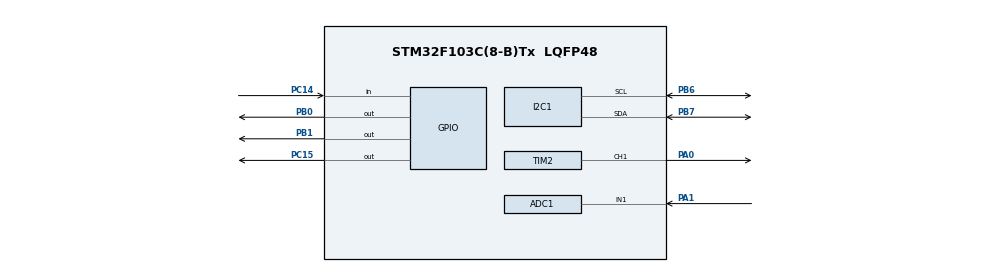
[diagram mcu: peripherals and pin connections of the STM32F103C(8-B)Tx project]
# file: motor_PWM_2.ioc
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ADC1.Channel-2\#ChannelRegularConversion=ADC_CHANNEL_1
ADC1.ContinuousConvMode=ENABLE
ADC1.NbrOfConversion=1
ADC1.NbrOfConversionFlag=1
ADC1.Rank-2\#ChannelRegularConversion=1
ADC1.SamplingTime-2\#ChannelRegularConversion=ADC_SAMPLETIME_1CYCLE_5
ADC1.master=1
Mcu.Family=STM32F1
Mcu.Name=STM32F103C(8-B)Tx
Mcu.Package=LQFP48
NVIC.PriorityGroup=NVIC_PRIORITYGROUP_4
PA0-WKUP.Signal=S_TIM2_CH1_ETR
PA1.Signal=ADCx_IN1
PA13.Mode=Serial_Wire
PA13.Signal=SYS_JTMS-SWDIO
PA14.Mode=Serial_Wire
PA14.Signal=SYS_JTCK-SWCLK
PB0.Signal=GPIO_Output
PB1.Signal=GPIO_Output
PB6.Mode=I2C
PB6.Signal=I2C1_SCL
PB7.Mode=I2C
PB7.Signal=I2C1_SDA
PC14-OSC32_IN.GPIO_PuPd=GPIO_PULLUP
PC14-OSC32_IN.Signal=GPIO_Input
PC15-OSC32_OUT.Signal=GPIO_Output
ProjectManager.HeapSize=0x200
ProjectManager.StackSize=0x400
ProjectManager.TargetToolchain=MDK-ARM V5.32
RCC.ADCPresc=RCC_ADCPCLK2_DIV4
RCC.AHBFreq_Value=8000000
RCC.APB1Freq_Value=8000000
RCC.APB1TimFreq_Value=8000000
RCC.APB2Freq_Value=8000000
RCC.APB2TimFreq_Value=8000000
RCC.HCLKFreq_Value=8000000
RCC.PLLMUL=RCC_PLL_MUL9
RCC.SYSCLKFreq_VALUE=8000000
RCC.USBFreq_Value=36000000
SH.ADCx_IN1.0=ADC1_IN1,IN1
SH.S_TIM2_CH1_ETR.0=TIM2_CH1,PWM Generation1 CH1
TIM2.AutoReloadPreload=TIM_AUTORELOAD_PRELOAD_ENABLE
TIM2.Channel-PWM\ Generation1\ CH1=TIM_CHANNEL_1
TIM2.Period=99
TIM2.Prescaler=35
VP_TIM2_VS_ClockSourceINT.Mode=Internal
board=custom

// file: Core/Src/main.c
/* USER CODE BEGIN Header */
/**
  ******************************************************************************
  * @file           : main.c
  * @brief          : Main program body
  ******************************************************************************
  * @attention
  *
  * Copyright (c) 2026 STMicroelectronics.
  * All rights reserved.
  *
  * This software is licensed under terms that can be found in the LICENSE file
  * in the root directory of this software component.
  * If no LICENSE file comes with this software, it is provided AS-IS.
  *
  ******************************************************************************
  */
/* USER CODE END Header */
#include "main.h"

/* USER CODE BEGIN Includes */
#include "ssd1306.h"
#include "speed.h"
/* USER CODE END Includes */

/* USER CODE BEGIN PTD */
#define AIN1_GPIO_Port GPIOB
#define AIN1_Pin GPIO_PIN_0
#define AIN2_GPIO_Port GPIOB
#define AIN2_Pin GPIO_PIN_1
/* USER CODE END PTD */

ADC_HandleTypeDef hadc1;

I2C_HandleTypeDef hi2c1;

TIM_HandleTypeDef htim2;

/* USER CODE BEGIN PV */
uint8_t speed;  // 全局变量，用于speed.c访问
/* USER CODE END PV */

void SystemClock_Config(void);
static void MX_GPIO_Init(void);
static void MX_TIM2_Init(void);
static void MX_ADC1_Init(void);
static void MX_I2C1_Init(void);
/* USER CODE BEGIN PFP */
void Motor_Forward(void);
void Motor_Backward(void);
void Motor_Stop(void);
void Motor_speed(uint8_t speed);
void Motor_Smooth_Stop(uint8_t speed);
/* USER CODE END PFP */

/* USER CODE BEGIN 0 */
//电机前进
void Motor_Forward(void)
{
    HAL_GPIO_WritePin(AIN1_GPIO_Port, AIN1_Pin, GPIO_PIN_SET);
    HAL_GPIO_WritePin(AIN2_GPIO_Port, AIN2_Pin, GPIO_PIN_RESET);
}

//电机后�??
void Motor_Backward(void)
{
    HAL_GPIO_WritePin(AIN1_GPIO_Port, AIN1_Pin, GPIO_PIN_RESET);
    HAL_GPIO_WritePin(AIN2_GPIO_Port, AIN2_Pin, GPIO_PIN_SET);
}

//电机停止
void Motor_Stop(void)
{
    HAL_GPIO_WritePin(AIN1_GPIO_Port, AIN1_Pin, GPIO_PIN_RESET);
    HAL_GPIO_WritePin(AIN2_GPIO_Port, AIN2_Pin, GPIO_PIN_RESET);
}

//设置电机速度
void Motor_speed(uint8_t speed)
{
    __HAL_TIM_SET_COMPARE(&htim2, TIM_CHANNEL_1, speed);
}

//控制电机平滑停止
void Motor_Smooth_Stop(uint8_t speed)
{
    for (uint8_t i = speed; i > 0; i--)
    {
        Motor_speed(i);
    }
}
/* USER CODE END 0 */

int main(void)
{

  /* MCU Configuration--------------------------------------------------------*/

  /* Reset of all peripherals, Initializes the Flash interface and the Systick. */
  HAL_Init();

  /* Configure the system clock */
  SystemClock_Config();

  /* Initialize all configured peripherals */
  MX_GPIO_Init();
  MX_TIM2_Init();
  MX_ADC1_Init();
  MX_I2C1_Init();
  /* USER CODE BEGIN 2 */

  // ========== 最小化诊断测试：纯GPIO翻转 ==========
  // 不依赖TIM/I2C/ADC/OLED任何外设

  // 关键修复：将PA0从TIM2复用模式改回普通GPIO输出模式！
  GPIO_InitTypeDef GPIO_InitStruct = {0};
  GPIO_InitStruct.Pin = GPIO_PIN_0;
  GPIO_InitStruct.Mode = GPIO_MODE_OUTPUT_PP;   // 普通推挽输出
  GPIO_InitStruct.Pull = GPIO_NOPULL;
  GPIO_InitStruct.Speed = GPIO_SPEED_FREQ_LOW;
  HAL_GPIO_Init(GPIOA, &GPIO_InitStruct);

  uint32_t count = 0;
  /* USER CODE END 2 */

  /* Infinite loop */
  /* USER CODE BEGIN WHILE */
  while (1)
  {
    count++;

    // 每500ms翻转一次所有输出引脚 (用LED闪烁+万用表可测)
    if (count % 500 == 0) {
      static uint8_t toggle = 0;
      toggle = !toggle;

      if (toggle) {
        // 状态1: 全部拉高 - 模拟电机正转
        HAL_GPIO_WritePin(GPIOB, GPIO_PIN_0, GPIO_PIN_SET);   // PB0=HIGH (AIN1)
        HAL_GPIO_WritePin(GPIOB, GPIO_PIN_1, GPIO_PIN_RESET); // PB1=LOW  (AIN2)
        HAL_GPIO_WritePin(GPIOA, GPIO_PIN_0, GPIO_PIN_SET);   // PA0=HIGH (PWM测试)
        HAL_GPIO_WritePin(GPIOC, GPIO_PIN_15, GPIO_PIN_SET);  // PC15=HIGH (LED亮)
      } else {
        // 状态2: 全部拉低
        HAL_GPIO_WritePin(GPIOB, GPIO_PIN_0, GPIO_PIN_RESET);
        HAL_GPIO_WritePin(GPIOB, GPIO_PIN_1, GPIO_PIN_RESET);
        HAL_GPIO_WritePin(GPIOA, GPIO_PIN_0, GPIO_PIN_RESET);
        HAL_GPIO_WritePin(GPIOC, GPIO_PIN_15, GPIO_PIN_RESET); // PC15=LOW (LED灭)
      }
    }

    HAL_Delay(1);

    /* USER CODE END WHILE */

  }
}

void SystemClock_Config(void)
{
  RCC_OscInitTypeDef RCC_OscInitStruct = {0};
  RCC_ClkInitTypeDef RCC_ClkInitStruct = {0};
  RCC_PeriphCLKInitTypeDef PeriphClkInit = {0};

  /** Initializes the RCC Oscillators according to the specified parameters
  * in the RCC_OscInitTypeDef structure.
  */
  RCC_OscInitStruct.OscillatorType = RCC_OSCILLATORTYPE_HSI;
  RCC_OscInitStruct.HSIState = RCC_HSI_ON;
  RCC_OscInitStruct.HSICalibrationValue = RCC_HSICALIBRATION_DEFAULT;
  RCC_OscInitStruct.PLL.PLLState = RCC_PLL_ON;
  RCC_OscInitStruct.PLL.PLLSource = RCC_PLLSOURCE_HSI_DIV2;
  RCC_OscInitStruct.PLL.PLLMUL = RCC_PLL_MUL9;
  if (HAL_RCC_OscConfig(&RCC_OscInitStruct) != HAL_OK)
  {
    Error_Handler();
  }

  /** Initializes the CPU, AHB and APB buses clocks
  */
  RCC_ClkInitStruct.ClockType = RCC_CLOCKTYPE_HCLK|RCC_CLOCKTYPE_SYSCLK
                              |RCC_CLOCKTYPE_PCLK1|RCC_CLOCKTYPE_PCLK2;
  RCC_ClkInitStruct.SYSCLKSource = RCC_SYSCLKSOURCE_PLLCLK;
  RCC_ClkInitStruct.AHBCLKDivider = RCC_SYSCLK_DIV1;
  RCC_ClkInitStruct.APB1CLKDivider = RCC_HCLK_DIV1;
  RCC_ClkInitStruct.APB2CLKDivider = RCC_HCLK_DIV1;

  if (HAL_RCC_ClockConfig(&RCC_ClkInitStruct, FLASH_LATENCY_1) != HAL_OK)
  {
    Error_Handler();
  }
  PeriphClkInit.PeriphClockSelection = RCC_PERIPHCLK_ADC;
  PeriphClkInit.AdcClockSelection = RCC_ADCPCLK2_DIV4;
  if (HAL_RCCEx_PeriphCLKConfig(&PeriphClkInit) != HAL_OK)
  {
    Error_Handler();
  }
}

static void MX_ADC1_Init(void)
{

  ADC_ChannelConfTypeDef sConfig = {0};

  /** Common config
  */
  hadc1.Instance = ADC1;
  hadc1.Init.ScanConvMode = ADC_SCAN_DISABLE;
  hadc1.Init.ContinuousConvMode = ENABLE;
  hadc1.Init.DiscontinuousConvMode = DISABLE;
  hadc1.Init.ExternalTrigConv = ADC_SOFTWARE_START;
  hadc1.Init.DataAlign = ADC_DATAALIGN_RIGHT;
  hadc1.Init.NbrOfConversion = 1;
  if (HAL_ADC_Init(&hadc1) != HAL_OK)
  {
    Error_Handler();
  }

  /** Configure Regular Channel
  */
  sConfig.Channel = ADC_CHANNEL_1;
  sConfig.Rank = ADC_REGULAR_RANK_1;
  sConfig.SamplingTime = ADC_SAMPLETIME_1CYCLE_5;
  if (HAL_ADC_ConfigChannel(&hadc1, &sConfig) != HAL_OK)
  {
    Error_Handler();
  }

}

static void MX_I2C1_Init(void)
{

  hi2c1.Instance = I2C1;
  hi2c1.Init.ClockSpeed = 100000;
  hi2c1.Init.DutyCycle = I2C_DUTYCYCLE_2;
  hi2c1.Init.OwnAddress1 = 0;
  hi2c1.Init.AddressingMode = I2C_ADDRESSINGMODE_7BIT;
  hi2c1.Init.DualAddressMode = I2C_DUALADDRESS_DISABLE;
  hi2c1.Init.OwnAddress2 = 0;
  hi2c1.Init.GeneralCallMode = I2C_GENERALCALL_DISABLE;
  hi2c1.Init.NoStretchMode = I2C_NOSTRETCH_DISABLE;
  if (HAL_I2C_Init(&hi2c1) != HAL_OK)
  {
    Error_Handler();
  }

}

static void MX_TIM2_Init(void)
{

  TIM_ClockConfigTypeDef sClockSourceConfig = {0};
  TIM_MasterConfigTypeDef sMasterConfig = {0};
  TIM_OC_InitTypeDef sConfigOC = {0};

  htim2.Instance = TIM2;
  htim2.Init.Prescaler = 35;
  htim2.Init.CounterMode = TIM_COUNTERMODE_UP;
  htim2.Init.Period = 99;
  htim2.Init.ClockDivision = TIM_CLOCKDIVISION_DIV1;
  htim2.Init.AutoReloadPreload = TIM_AUTORELOAD_PRELOAD_ENABLE;
  if (HAL_TIM_Base_Init(&htim2) != HAL_OK)
  {
    Error_Handler();
  }
  sClockSourceConfig.ClockSource = TIM_CLOCKSOURCE_INTERNAL;
  if (HAL_TIM_ConfigClockSource(&htim2, &sClockSourceConfig) != HAL_OK)
  {
    Error_Handler();
  }
  if (HAL_TIM_PWM_Init(&htim2) != HAL_OK)
  {
    Error_Handler();
  }
  sMasterConfig.MasterOutputTrigger = TIM_TRGO_RESET;
  sMasterConfig.MasterSlaveMode = TIM_MASTERSLAVEMODE_DISABLE;
  if (HAL_TIMEx_MasterConfigSynchronization(&htim2, &sMasterConfig) != HAL_OK)
  {
    Error_Handler();
  }
  sConfigOC.OCMode = TIM_OCMODE_PWM1;
  sConfigOC.Pulse = 0;
  sConfigOC.OCPolarity = TIM_OCPOLARITY_HIGH;
  sConfigOC.OCFastMode = TIM_OCFAST_DISABLE;
  if (HAL_TIM_PWM_ConfigChannel(&htim2, &sConfigOC, TIM_CHANNEL_1) != HAL_OK)
  {
    Error_Handler();
  }
  HAL_TIM_MspPostInit(&htim2);

}

static void MX_GPIO_Init(void)
{
  GPIO_InitTypeDef GPIO_InitStruct = {0};

  /* GPIO Ports Clock Enable */
  __HAL_RCC_GPIOC_CLK_ENABLE();
  __HAL_RCC_GPIOA_CLK_ENABLE();
  __HAL_RCC_GPIOB_CLK_ENABLE();

  /*Configure GPIO pin Output Level */
  HAL_GPIO_WritePin(GPIOC, GPIO_PIN_15, GPIO_PIN_RESET);

  /*Configure GPIO pin Output Level */
  HAL_GPIO_WritePin(GPIOB, GPIO_PIN_0|GPIO_PIN_1, GPIO_PIN_RESET);

  /*Configure GPIO pin : PC14 */
  GPIO_InitStruct.Pin = GPIO_PIN_14;
  GPIO_InitStruct.Mode = GPIO_MODE_INPUT;
  GPIO_InitStruct.Pull = GPIO_PULLUP;
  HAL_GPIO_Init(GPIOC, &GPIO_InitStruct);

  /*Configure GPIO pin : PC15 */
  GPIO_InitStruct.Pin = GPIO_PIN_15;
  GPIO_InitStruct.Mode = GPIO_MODE_OUTPUT_PP;
  GPIO_InitStruct.Pull = GPIO_NOPULL;
  GPIO_InitStruct.Speed = GPIO_SPEED_FREQ_LOW;
  HAL_GPIO_Init(GPIOC, &GPIO_InitStruct);

  /*Configure GPIO pins : PB0 PB1 */
  GPIO_InitStruct.Pin = GPIO_PIN_0|GPIO_PIN_1;
  GPIO_InitStruct.Mode = GPIO_MODE_OUTPUT_PP;
  GPIO_InitStruct.Pull = GPIO_NOPULL;
  GPIO_InitStruct.Speed = GPIO_SPEED_FREQ_LOW;
  HAL_GPIO_Init(GPIOB, &GPIO_InitStruct);

}

void Error_Handler(void)
{
  __disable_irq();
  while (1)
  {
  }
}
